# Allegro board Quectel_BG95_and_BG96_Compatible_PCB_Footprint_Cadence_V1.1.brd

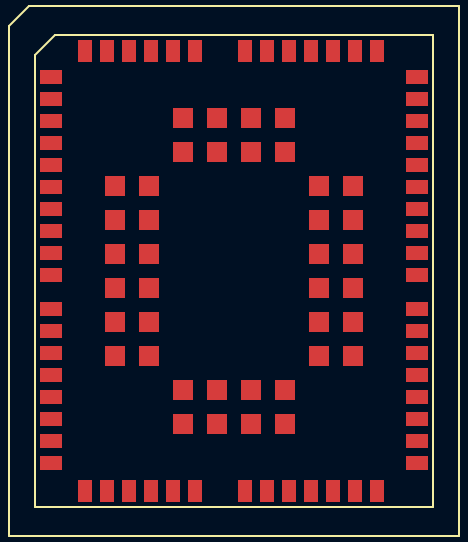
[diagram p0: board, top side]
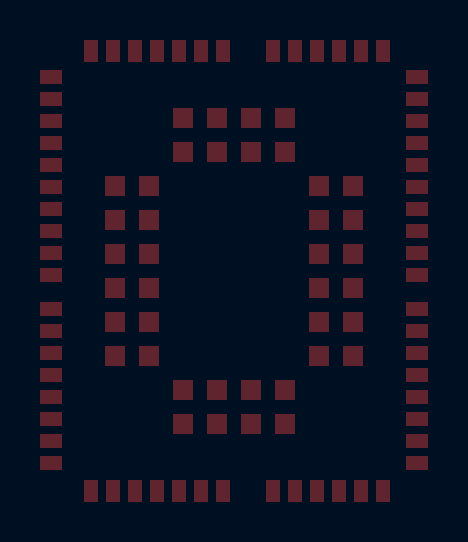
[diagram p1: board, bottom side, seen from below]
No outline. copper layers: TOP, BOTTOM. Coordinates in mm from the lowest, leftmost part position.

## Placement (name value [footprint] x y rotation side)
NOREF  -  [unnamed]  0 0 0 top

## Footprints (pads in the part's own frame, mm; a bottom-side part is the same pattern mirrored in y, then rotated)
unnamed
  rect 1.1x0.7 smd: 1(-9.15,9.7) 2(-9.15,8.6) 3(-9.15,7.5) 4(-9.15,6.4) 5(-9.15,5.3) 6(-9.15,4.2) 7(-9.15,3.1) 8(-9.15,2) 9(-9.15,0.9) 10(-9.15,-0.2) 11(-9.15,-1.9) 12(-9.15,-3) 13(-9.15,-4.1) 14(-9.15,-5.2) 15(-9.15,-6.3) 16(-9.15,-7.4) 17(-9.15,-8.5) 18(-9.15,-9.6) 32(9.15,-9.6) 33(9.15,-8.5) 34(9.15,-7.4) 35(9.15,-6.3) 36(9.15,-5.2) 37(9.15,-4.1) 38(9.15,-3) 39(9.15,-1.9) 40(9.15,-0.2) 41(9.15,0.9) 42(9.15,2) 43(9.15,3.1) 44(9.15,4.2) 45(9.15,5.3) 46(9.15,6.4) 47(9.15,7.5) 48(9.15,8.6) 49(9.15,9.7)
  rect 0.7x1.1 smd: 19(-7.45,-11) 20(-6.35,-11) 21(-5.25,-11) 22(-4.15,-11) 23(-3.05,-11) 24(-1.95,-11) 25(0.55,-11) 26(1.65,-11) 27(2.75,-11) 28(3.85,-11) 29(4.95,-11) 30(6.05,-11) 31(7.15,-11) 50(7.15,11) 51(6.05,11) 52(4.95,11) 53(3.85,11) 54(2.75,11) 55(1.65,11) 56(0.55,11) 57(-1.95,11) 58(-3.05,11) 59(-4.15,11) 60(-5.25,11) 61(-6.35,11) 62(-7.45,11)
  rect 1x1 smd: 63(-5.95,4.25) 64(-5.95,2.55) 65(-5.95,0.85) 66(-5.95,-0.85) 67(-5.95,-2.55) 68(-5.95,-4.25) 69(-2.55,-7.65) 70(-0.85,-7.65) 71(0.85,-7.65) 72(2.55,-7.65) 73(5.95,-4.25) 74(5.95,-2.55) 75(5.95,-0.85) 76(5.95,0.85) 77(5.95,2.55) 78(5.95,4.25) 79(2.55,7.65) 80(0.85,7.65) 81(-0.85,7.65) 82(-2.55,7.65) 83(-4.25,4.25) 84(-4.25,2.55) 85(-4.25,0.85) 86(-4.25,-0.85) 87(-4.25,-2.55) 88(-4.25,-4.25) 89(-2.55,-5.95) 90(-0.85,-5.95) 91(0.85,-5.95) 92(2.55,-5.95) 93(4.25,-4.25) 94(4.25,-2.55) 95(4.25,-0.85) 96(4.25,0.85) 97(4.25,2.55) 98(4.25,4.25) 99(2.55,5.95) 100(0.85,5.95) 101(-0.85,5.95) 102(-2.55,5.95)

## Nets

Pads without a net: NOREF 1 2 3 4 5 6 7 8 9 10 11 12 13 14 15 16 17 18 19 20 21 22 23 24 25 26 27 28 29 30 31 32 33 34 35 36 37 38 39 40 41 42 43 44 45 46 47 48 49 50 51 52 53 54 55 56 57 58 59 60 61 62 63 64 65 66 67 68 69 70 71 72 73 74 75 76 77 78 79 80 81 82 83 84 85 86 87 88 89 90 91 92 93 94 95 96 97 98 99 100 101 102
